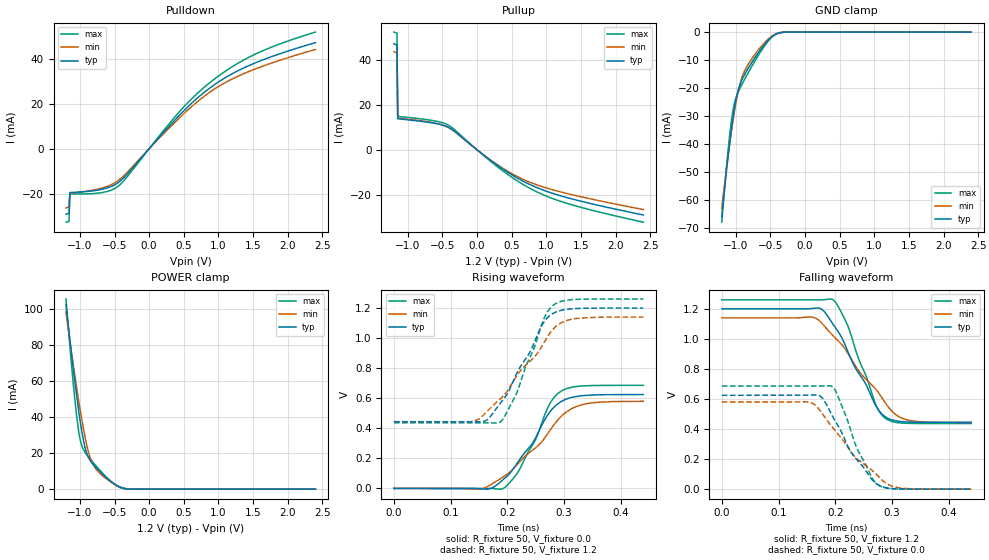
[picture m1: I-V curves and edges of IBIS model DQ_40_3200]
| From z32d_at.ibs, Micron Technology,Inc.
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| MODEL DQ_40_3200 (40 Ohm Data I/O with no ODT, 1600-3200Mbps)
[Model]   DQ_40_3200
Model_type   I/O
Vinl = 905.000mV
Vinh = 1015.000mV
Vmeas = 960.000mV
Vref = 1200.000mV
Cref = 0.0pF
Rref = 50.000Ohm
|   typ   min   max
|C_comp   0.636pF   0.586pF   0.686pF
C_comp_pullup   0.318pF   0.293pF   0.343pF
C_comp_pulldown   0.318pF   0.293pF   0.343pF
[Model Spec]
| Timing spec test load voltage corners
Vref   1.2000V   1.1400V   1.2600V
| Dynamic Overshoot Parameters from DDR4 Specification
|D_overshoot_ampl_h   0.40   NA   NA
|D_overshoot_ampl_l   0.40   NA   NA
|D_overshoot_area_h   0.0800n   NA   NA
|D_overshoot_area_l   0.0800n   NA   NA
[Voltage Range]   1.2000V   1.1400V   1.2600V
| Junction Temperature (Ambient temp is 35C typ, 105C min, -40C max)
[Temperature Range]   50.0   120.0   -40.0
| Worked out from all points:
|   slope of the pulldown table from 0 to 0.18 V, typ, clamps not added: 28.6 ohm
|   slope of the pullup table from 0 to 0.18 V, typ, clamps not added: 41.6 ohm
|   GND clamp passes 1 mA (typ) near -0.44 V on its own axis
|   POWER clamp passes 1 mA (typ) near -0.41 V on its own axis
|   rising waveform, R_fixture 50, V_fixture 0.0: 20-80 % time 63.6ps typ, 84.6ps min, 49.8ps max; typ from 0 V to 0.625 V
|   rising waveform, R_fixture 50, V_fixture 1.2: 20-80 % time 62.3ps typ, 85.6ps min, 48.6ps max; typ from 0.444 V to 1.2 V
|   falling waveform, R_fixture 50, V_fixture 1.2: 20-80 % time 61.1ps typ, 85.3ps min, 46.3ps max; typ from 1.2 V to 0.444 V
|   falling waveform, R_fixture 50, V_fixture 0.0: 20-80 % time 60.7ps typ, 83.5ps min, 45.1ps max; typ from 0.625 V to 0 V
[Pulldown]
|   Voltage   I(typ)   I(min)   I(max)
-1.2V     -29.12mA   -26.36mA   -32.71mA
-1.156V   -28.8mA    -26.03mA   -32.39mA
-1.145V   -19.51mA   -19.79mA   -20.16mA
-698.2mV  -18.17mA   -17.64mA   -19.61mA
-447.3mV  -15.08mA   -14.18mA   -16.69mA
-338.2mV  -11.99mA   -11.17mA   -13.27mA
469.1mV   15.9mA     14.67mA    17.58mA
698.2mV   22.62mA    20.99mA    24.73mA
938.2mV   28.41mA    26.49mA    30.92mA
1.211V    33.57mA    31.24mA    36.74mA
1.516V    38.02mA    35.32mA    41.88mA
2.4V      47.23mA    44.21mA    51.93mA
[GND Clamp]
|   Voltage   I(typ)   I(min)   I(max)
-1.2V     -66.16mA   -63.19mA   -68.09mA
-1.135V   -50.09mA   -49.27mA   -48.84mA
-1.091V   -40.55mA   -40.91mA   -37.85mA
-1.047V   -32.05mA   -33.18mA   -29.3mA
-1.004V   -25.21mA   -26.37mA   -24.13mA
-970.9mV  -21.44mA   -22.14mA   -21.89mA
-927.3mV  -18.1mA    -17.66mA   -19.59mA
-850.9mV  -14.3mA    -12.92mA   -15.99mA
-632.7mV  -6.061mA   -5.168mA   -6.759mA
-447.3mV  -1.181mA   -1.003mA   -1.122mA
-250.9mV  -9.403uA   -17.03uA   310.9nA
2.4V      0A         0A         0A
[Pullup]
|   Voltage   I(typ)   I(min)   I(max)
-1.2V     47.33mA    43.8mA     52.54mA
-1.156V   46.84mA    43.28mA    52.08mA
-1.145V   13.94mA    14.01mA    14.91mA
-676.4mV  12.17mA    12.32mA    13.24mA
-425.5mV  10.24mA    10.08mA    11.21mA
-316.4mV  8.104mA    7.94mA     8.758mA
43.64mV   -1.073mA   -1.039mA   -1.164mA
370.9mV   -8.572mA   -8.203mA   -9.376mA
621.8mV   -13.28mA   -12.55mA   -14.64mA
949.1mV   -17.88mA   -16.51mA   -19.98mA
1.462V    -22.63mA   -20.68mA   -25.34mA
2.4V      -29.08mA   -26.66mA   -32.28mA
[POWER Clamp]
|   Voltage   I(typ)   I(min)   I(max)
-1.2V     102.5mA    98.29mA    105.3mA
-1.135V   79.77mA    79.49mA    75.19mA
-1.069V   58.73mA    62.1mA     48.42mA
-1.015V   42.78mA    48.44mA    31.4mA
-981.8mV  34.36mA    40.79mA    25.35mA
-938.2mV  25.27mA    31.47mA    21.3mA
-905.5mV  20.47mA    25.33mA    19.42mA
-818.2mV  14.14mA    14.34mA    15.22mA
-709.1mV  9.665mA    8.746mA    10.4mA
-501.8mV  2.908mA    2.683mA    2.742mA
-250.9mV  22.56uA    45.53uA    -929.3nA
2.4V      0A         0A         0A
[Ramp]
|   typ   min   max
| 20% - 80%
dV/dt_r   374.75m/63.58p   347.77m/84.56p   411.51m/49.80p
dV/dt_f   453.55m/61.15p   417.79m/85.32p   494.02m/46.29p
| Slew rate: Power terminated
|SR_r[V/ns]   7.28   4.88   10.18
|SR_f[V/ns]   7.42   4.90   10.67
| 25% - 75%
|dV/dt_r   312.29m/52.61p   289.81m/70.66p   342.92m/41.18p
|dV/dt_f   377.96m/50.69p   348.16m/70.02p   411.68m/38.60p
| Slew rate: Power terminated
|SR_r[V/ns]   7.36   4.93   10.29
|SR_f[V/ns]   7.46   4.97   10.67
R_load = 50
[Rising Waveform]
R_fixture = 50
V_fixture = 0.0
|   Time   V(typ)   V(min)   V(max)
0s        6.048uV    19.72uV    354.8nV
151ps     -1.811mV   -3.906mV   40.26uV
172ps     1.347mV    26.69mV    -349.1uV
192ps     56.09mV    74.04mV    -1.218mV
220ps     183mV      170.1mV    115.4mV
250ps     337mV      270.6mV    326.1mV
273ps     498.3mV    374.4mV    549.3mV
292ps     570.9mV    467.2mV    639.7mV
336ps     618.4mV    560.6mV    682.6mV
440ps     624.6mV    579.6mV    685.8mV
[Rising Waveform]
R_fixture   = 50
V_fixture   = 1.2
V_fixture_min = 1.14
V_fixture_max = 1.26
|   Time   V(typ)   V(min)   V(max)
0s        444.1mV    443.6mV    436.6mV
140ps     443.6mV    446.5mV    436.6mV
164ps     455.2mV    511.7mV    436.6mV
187ps     563.5mV    593.3mV    440.8mV
215ps     752.6mV    739.8mV    620.5mV
240ps     907.8mV    846.2mV    872.8mV
264ps     1.104V     965mV      1.125V
280ps     1.163V     1.056V     1.216V
320ps     1.197V     1.13V      1.257V
440ps     1.2V       1.14V      1.26V
[Falling Waveform]
R_fixture   = 50
V_fixture   = 1.2
V_fixture_min = 1.14
V_fixture_max = 1.26
|   Time   V(typ)   V(min)   V(max)
0s        1.2V       1.14V      1.26V
159ps     1.202V     1.145V     1.26V
176ps     1.198V     1.106V     1.26V
195ps     1.104V     1.025V     1.263V
220ps     936.8mV    918.6mV    1.107V
270ps     566.7mV    672.3mV    576.6mV
286ps     487.8mV    587.6mV    478.6mV
305ps     456.3mV    501.5mV    445.8mV
328ps     446.7mV    460.1mV    438.1mV
440ps     444.1mV    443.7mV    436.6mV
[Falling Waveform]
R_fixture = 50
V_fixture = 0.0
|   Time   V(typ)   V(min)   V(max)
0s        624.6mV    579.8mV    685.9mV
154ps     625.9mV    578.5mV    685.8mV
175ps     614.8mV    514.1mV    686.2mV
193ps     500.6mV    420.5mV    685.8mV
203ps     434.8mV    376.1mV    635mV
229ps     239.7mV    241.7mV    371.7mV
241ps     184.3mV    194.6mV    251.2mV
275ps     29.84mV    88.51mV    30.16mV
313ps     1.736mV    9.083mV    942.9uV
440ps     6.181uV    24.11uV    369nV
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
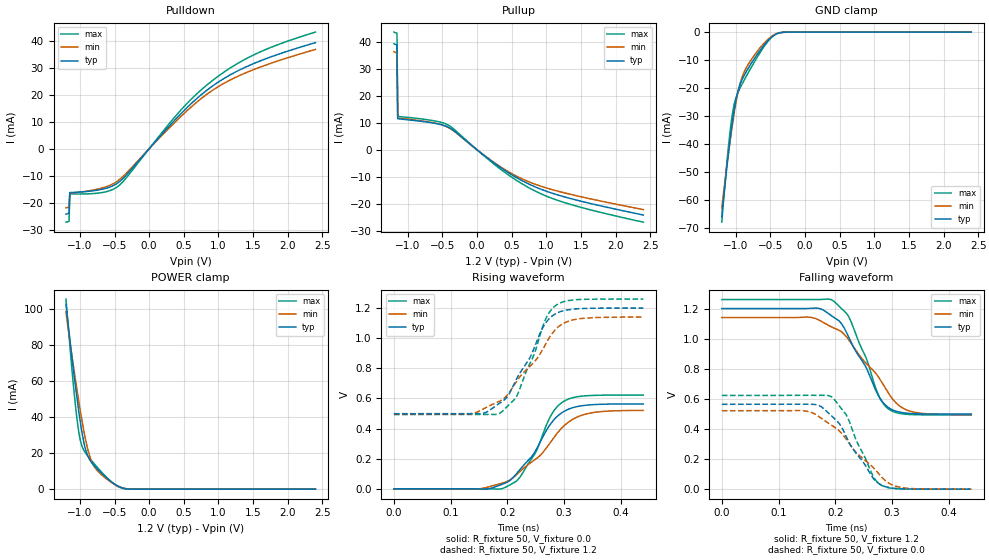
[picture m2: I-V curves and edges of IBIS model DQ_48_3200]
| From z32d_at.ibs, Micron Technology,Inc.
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| MODEL DQ_48_3200 (48 Ohm Data I/O with no ODT, 1600-3200Mbps)
[Model]   DQ_48_3200
Model_type   I/O
Vinl = 905.000mV
Vinh = 1015.000mV
Vmeas = 960.000mV
Vref = 1200.000mV
Cref = 0.0pF
Rref = 50.000Ohm
|   typ   min   max
|C_comp   0.636pF   0.586pF   0.686pF
C_comp_pullup   0.318pF   0.293pF   0.343pF
C_comp_pulldown   0.318pF   0.293pF   0.343pF
[Model Spec]
| Timing spec test load voltage corners
Vref   1.2000V   1.1400V   1.2600V
| Dynamic Overshoot Parameters from DDR4 Specification
|D_overshoot_ampl_h   0.40   NA   NA
|D_overshoot_ampl_l   0.40   NA   NA
|D_overshoot_area_h   0.0800n   NA   NA
|D_overshoot_area_l   0.0800n   NA   NA
[Voltage Range]   1.2000V   1.1400V   1.2600V
| Junction Temperature (Ambient temp is 35C typ, 105C min, -40C max)
[Temperature Range]   50.0   120.0   -40.0
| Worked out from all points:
|   slope of the pulldown table from 0 to 0.18 V, typ, clamps not added: 34.3 ohm
|   slope of the pullup table from 0 to 0.18 V, typ, clamps not added: 49.8 ohm
|   GND clamp passes 1 mA (typ) near -0.44 V on its own axis
|   POWER clamp passes 1 mA (typ) near -0.41 V on its own axis
|   rising waveform, R_fixture 50, V_fixture 0.0: 20-80 % time 61.7ps typ, 80.3ps min, 48.6ps max; typ from 0 V to 0.564 V
|   rising waveform, R_fixture 50, V_fixture 1.2: 20-80 % time 56.5ps typ, 74.9ps min, 45ps max; typ from 0.499 V to 1.2 V
|   falling waveform, R_fixture 50, V_fixture 1.2: 20-80 % time 56.4ps typ, 75.9ps min, 45.2ps max; typ from 1.2 V to 0.499 V
|   falling waveform, R_fixture 50, V_fixture 0.0: 20-80 % time 56.3ps typ, 79.4ps min, 43.6ps max; typ from 0.564 V to 0 V
[Pulldown]
|   Voltage   I(typ)   I(min)   I(max)
-1.2V     -24.27mA   -21.97mA   -27.26mA
-1.156V   -24mA      -21.69mA   -26.99mA
-1.145V   -16.26mA   -16.49mA   -16.8mA
-665.5mV  -14.96mA   -14.47mA   -16.2mA
-534.5mV  -13.86mA   -13.19mA   -15.23mA
-436.4mV  -12.37mA   -11.61mA   -13.68mA
425.5mV   12.1mA     11.15mA    13.4mA
643.6mV   17.6mA     16.3mA     19.29mA
927.3mV   23.48mA    21.9mA     25.55mA
1.2V      27.83mA    25.89mA    30.45mA
1.527V    31.8mA     29.55mA    35.03mA
2.4V      39.36mA    36.85mA    43.27mA
[GND Clamp]
|   Voltage   I(typ)   I(min)   I(max)
-1.2V     -66.16mA   -63.19mA   -68.09mA
-1.135V   -50.09mA   -49.27mA   -48.85mA
-1.091V   -40.54mA   -40.91mA   -37.85mA
-1.058V   -34.05mA   -35.04mA   -31.11mA
-1.015V   -26.75mA   -27.97mA   -25.14mA
-970.9mV  -21.46mA   -22.07mA   -21.88mA
-938.2mV  -18.78mA   -18.62mA   -20.13mA
-861.8mV  -14.78mA   -13.45mA   -16.49mA
-654.5mV  -6.796mA   -5.82mA    -7.607mA
-458.2mV  -1.354mA   -1.154mA   -1.328mA
-261.8mV  -15.07uA   -22.38uA   -1.874uA
2.4V      0A         0A         0A
[Pullup]
|   Voltage   I(typ)   I(min)   I(max)
-1.2V     39.44mA    36.5mA     43.78mA
-1.156V   39.03mA    36.07mA    43.4mA
-1.145V   11.61mA    11.67mA    12.43mA
-654.5mV  10.06mA    10.17mA    10.94mA
-425.5mV  8.536mA    8.416mA    9.339mA
-327.3mV  6.972mA    6.829mA    7.536mA
54.55mV   -1.117mA   -1.08mA    -1.215mA
381.8mV   -7.325mA   -7.008mA   -8.015mA
687.3mV   -11.95mA   -11.24mA   -13.21mA
949.1mV   -14.91mA   -13.76mA   -16.65mA
1.462V    -18.86mA   -17.23mA   -21.12mA
2.4V      -24.24mA   -22.22mA   -26.9mA
[POWER Clamp]
|   Voltage   I(typ)   I(min)   I(max)
-1.2V     102.5mA    98.29mA    105.3mA
-1.135V   79.77mA    79.49mA    75.19mA
-1.069V   58.73mA    62.1mA     48.4mA
-1.015V   42.76mA    48.44mA    31.44mA
-981.8mV  34.37mA    40.78mA    25.34mA
-938.2mV  25.23mA    31.42mA    21.29mA
-905.5mV  20.47mA    25.3mA     19.42mA
-818.2mV  14.14mA    14.34mA    15.22mA
-709.1mV  9.665mA    8.746mA    10.4mA
-501.8mV  2.9mA      2.681mA    2.745mA
-261.8mV  34uA       56.74uA    4.604uA
2.4V      0A         0A         0A
[Ramp]
|   typ   min   max
| 20% - 80%
dV/dt_r   338.19m/61.67p   312.42m/80.31p   373.57m/48.65p
dV/dt_f   420.87m/56.38p   386.39m/75.92p   460.07m/45.24p
| Slew rate: Power terminated
|SR_r[V/ns]   7.46   5.16   10.22
|SR_f[V/ns]   7.46   5.09   10.17
| 25% - 75%
|dV/dt_r   281.82m/49.79p   260.35m/66.06p   311.31m/39.25p
|dV/dt_f   350.73m/47.52p   321.99m/64.22p   383.39m/37.68p
| Slew rate: Power terminated
|SR_r[V/ns]   7.39   5.07   10.20
|SR_f[V/ns]   7.38   5.01   10.17
R_load = 50
[Rising Waveform]
R_fixture = 50
V_fixture = 0.0
|   Time   V(typ)   V(min)   V(max)
0s        6.769uV    21.94uV    398.2nV
146ps     -811.3uV   -1.787mV   8.918uV
193ps     32.9mV     39.55mV    3.811mV
207ps     62.53mV    64.93mV    30.62mV
223ps     131.7mV    116.7mV    80.82mV
251ps     260.6mV    199.4mV    248.6mV
277ps     433.9mV    313.8mV    486.6mV
298ps     509.5mV    410.4mV    577.1mV
343ps     556.6mV    500.4mV    618.8mV
440ps     563.7mV    520.7mV    622.6mV
[Rising Waveform]
R_fixture   = 50
V_fixture   = 1.2
V_fixture_min = 1.14
V_fixture_max = 1.26
|   Time   V(typ)   V(min)   V(max)
0s        498.5mV    495.9mV    493.2mV
135ps     498.3mV    498mV      493.2mV
186ps     566.9mV    580.6mV    500.2mV
201ps     616.4mV    627.6mV    551.7mV
217ps     734.3mV    717.2mV    618.8mV
248ps     939.9mV    843.6mV    899.5mV
267ps     1.098V     957.6mV    1.122V
286ps     1.164V     1.062V     1.219V
330ps     1.197V     1.131V     1.258V
440ps     1.2V       1.14V      1.26V
[Falling Waveform]
R_fixture   = 50
V_fixture   = 1.2
V_fixture_min = 1.14
V_fixture_max = 1.26
|   Time   V(typ)   V(min)   V(max)
0s        1.2V       1.14V      1.26V
153ps     1.201V     1.143V     1.26V
193ps     1.153V     1.079V     1.259V
211ps     1.1V       1.046V     1.2V
224ps     1.008V     991.8mV    1.145V
255ps     804.3mV    834.2mV    867mV
275ps     629.7mV    752.1mV    635.9mV
292ps     547.6mV    648.3mV    538.7mV
332ps     502.8mV    518.3mV    495.8mV
440ps     498.5mV    496mV      493.2mV
[Falling Waveform]
R_fixture = 50
V_fixture = 0.0
|   Time   V(typ)   V(min)   V(max)
0s        563.7mV    521.1mV    622.6mV
147ps     564.2mV    519.4mV    622.6mV
171ps     556.2mV    482.4mV    622.9mV
191ps     495.2mV    431.5mV    618.5mV
208ps     431.6mV    383.8mV    548.8mV
220ps     344.5mV    328.7mV    489.3mV
265ps     83.15mV    151.2mV    100.1mV
280ps     30.02mV    88.21mV    29.53mV
320ps     1.953mV    9.203mV    1.095mV
440ps     7.785uV    31.9uV     515.6nV
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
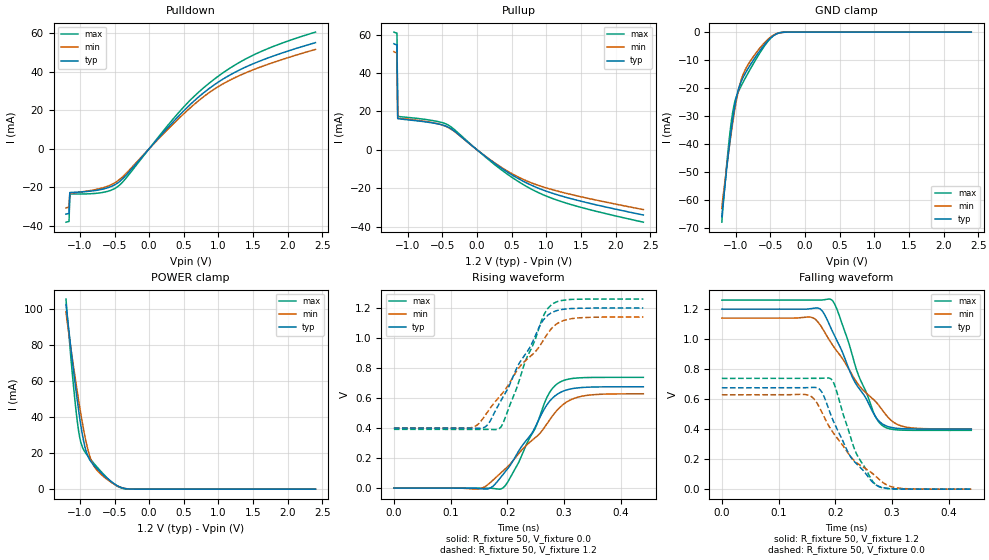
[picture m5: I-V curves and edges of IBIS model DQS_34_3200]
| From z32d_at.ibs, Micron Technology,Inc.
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| MODEL DQS_34_3200 (34 Ohm Data Strobe I/O with no ODT, 1600-3200Mbps)
[Model]   DQS_34_3200
Model_type   I/O
Vinl = 905.000mV
Vinh = 1015.000mV
Vmeas = 960.000mV
Vref = 1200.000mV
Cref = 0.0pF
Rref = 50.000Ohm
|   typ   min   max
|C_comp   0.636pF   0.586pF   0.686pF
C_comp_pullup   0.318pF   0.293pF   0.343pF
C_comp_pulldown   0.318pF   0.293pF   0.343pF
[Model Spec]
| Timing spec test load voltage corners
Vref   1.2000V   1.1400V   1.2600V
| Dynamic Overshoot Parameters from DDR4 Specification
|D_overshoot_ampl_h   0.40   NA   NA
|D_overshoot_ampl_l   0.40   NA   NA
|D_overshoot_area_h   0.0800n   NA   NA
|D_overshoot_area_l   0.0800n   NA   NA
[Voltage Range]   1.2000V   1.1400V   1.2600V
| Junction Temperature (Ambient temp is 35C typ, 105C min, -40C max)
[Temperature Range]   50.0   120.0   -40.0
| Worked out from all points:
|   slope of the pulldown table from 0 to 0.18 V, typ, clamps not added: 24.5 ohm
|   slope of the pullup table from 0 to 0.18 V, typ, clamps not added: 35.6 ohm
|   GND clamp passes 1 mA (typ) near -0.44 V on its own axis
|   POWER clamp passes 1 mA (typ) near -0.41 V on its own axis
|   rising waveform, R_fixture 50, V_fixture 0.0: 20-80 % time 65.4ps typ, 88.3ps min, 51.3ps max; typ from 0 V to 0.675 V
|   rising waveform, R_fixture 50, V_fixture 1.2: 20-80 % time 66.8ps typ, 91.7ps min, 51.8ps max; typ from 0.4 V to 1.2 V
|   falling waveform, R_fixture 50, V_fixture 1.2: 20-80 % time 63.8ps typ, 89ps min, 48.9ps max; typ from 1.2 V to 0.4 V
|   falling waveform, R_fixture 50, V_fixture 0.0: 20-80 % time 59ps typ, 80.5ps min, 44.9ps max; typ from 0.676 V to 0 V
[Pulldown]
|   Voltage   I(typ)   I(min)   I(max)
-1.2V     -33.97mA   -30.75mA   -38.16mA
-1.156V   -33.6mA    -30.37mA   -37.79mA
-1.145V   -22.76mA   -23.09mA   -23.52mA
-665.5mV  -20.94mA   -20.25mA   -22.68mA
-534.5mV  -19.41mA   -18.46mA   -21.32mA
-436.4mV  -17.3mA    -16.23mA   -19.17mA
447.3mV   17.75mA    16.36mA    19.64mA
687.3mV   26.05mA    24.16mA    28.48mA
960mV     33.69mA    31.42mA    36.67mA
1.222V    39.38mA    36.64mA    43.11mA
1.527V    44.52mA    41.36mA    49.04mA
2.4V      55.1mA     51.58mA    60.58mA
[GND Clamp]
|   Voltage   I(typ)   I(min)   I(max)
-1.2V     -66.16mA   -63.19mA   -68.09mA
-1.135V   -50.09mA   -49.27mA   -48.84mA
-1.091V   -40.54mA   -40.91mA   -37.85mA
-1.047V   -32.06mA   -33.18mA   -29.28mA
-1.004V   -25.24mA   -26.41mA   -24.15mA
-960mV    -20.46mA   -20.87mA   -21.27mA
-927.3mV  -18.11mA   -17.71mA   -19.59mA
-840mV    -13.84mA   -12.43mA   -15.5mA
-632.7mV  -6.06mA    -5.168mA   -6.758mA
-458.2mV  -1.359mA   -1.153mA   -1.332mA
-250.9mV  -9.002uA   -15.24uA   1.741uA
2.4V      0A         0A         0A
[Pullup]
|   Voltage   I(typ)   I(min)   I(max)
-1.2V     55.21mA    51.1mA     61.29mA
-1.156V   54.64mA    50.49mA    60.76mA
-1.145V   16.26mA    16.34mA    17.4mA
-643.6mV  14.02mA    14.17mA    15.25mA
-414.5mV  11.76mA    11.58mA    12.86mA
-316.4mV  9.458mA    9.262mA    10.21mA
87.27mV   -2.487mA   -2.407mA   -2.71mA
403.6mV   -10.78mA   -10.31mA   -11.8mA
643.6mV   -15.92mA   -15.01mA   -17.57mA
960mV     -21.02mA   -19.39mA   -23.48mA
1.484V    -26.6mA    -24.3mA    -29.78mA
2.4V      -33.93mA   -31.11mA   -37.66mA
[POWER Clamp]
|   Voltage   I(typ)   I(min)   I(max)
-1.2V     102.5mA    98.29mA    105.3mA
-1.135V   79.77mA    79.49mA    75.19mA
-1.08V    62.13mA    64.93mA    52.54mA
-1.036V   48.91mA    53.79mA    37.32mA
-992.7mV  37.04mA    43.27mA    27.02mA
-916.4mV  21.89mA    27.24mA    20mA
-861.8mV  16.57mA    18.83mA    17.26mA
-818.2mV  14.14mA    14.37mA    15.22mA
-720mV    10.08mA    9.153mA    10.86mA
-512.7mV  3.198mA    2.931mA    3.061mA
-250.9mV  21.9uA     40.66uA    -1.736uA
2.4V      0A         0A         0A
[Ramp]
|   typ   min   max
| 20% - 80%
dV/dt_r   405.29m/65.42p   377.33m/88.34p   442.96m/51.27p
dV/dt_f   479.80m/63.86p   443.25m/88.97p   520.92m/48.87p
| Slew rate: Power terminated
|SR_r[V/ns]   7.18   4.83   10.05
|SR_f[V/ns]   7.51   4.98   10.66
| 25% - 75%
|dV/dt_r   337.74m/54.25p   314.44m/73.48p   369.13m/42.54p
|dV/dt_f   399.83m/53.48p   369.38m/74.60p   434.10m/40.83p
| Slew rate: Power terminated
|SR_r[V/ns]   7.13   4.75   9.99
|SR_f[V/ns]   7.48   4.95   10.63
R_load = 50
[Rising Waveform]
R_fixture = 50
V_fixture = 0.0
|   Time   V(typ)   V(min)   V(max)
0s        5.466uV    18.08uV    320nV
150ps     -2.78mV    -5.018mV   66.59uV
171ps     2.747mV    40.23mV    -649.6uV
190ps     79.57mV    106.5mV    -3.675mV
217ps     227.7mV    215.5mV    148mV
250ps     412.1mV    337.3mV    405.2mV
270ps     555.5mV    429.1mV    605.2mV
287ps     622.8mV    515.6mV    691.8mV
332ps     670.6mV    612.8mV    735.9mV
440ps     675.5mV    628.9mV    738.3mV
[Rising Waveform]
R_fixture   = 50
V_fixture   = 1.2
V_fixture_min = 1.14
V_fixture_max = 1.26
|   Time   V(typ)   V(min)   V(max)
0s        400.3mV    401.2mV    391.8mV
139ps     399.6mV    405.4mV    391.8mV
164ps     417mV      501.4mV    391.7mV
185ps     557.9mV    603.9mV    395.1mV
194ps     615.4mV    644.6mV    446mV
222ps     838mV      809.6mV    729.4mV
259ps     1.094V     957.7mV    1.102V
276ps     1.164V     1.055V     1.216V
314ps     1.197V     1.13V      1.258V
440ps     1.2V       1.14V      1.26V
[Falling Waveform]
R_fixture   = 50
V_fixture   = 1.2
V_fixture_min = 1.14
V_fixture_max = 1.26
|   Time   V(typ)   V(min)   V(max)
0s        1.2V       1.14V      1.26V
156ps     1.203V     1.147V     1.26V
175ps     1.196V     1.086V     1.26V
192ps     1.077V     979.4mV    1.265V
205ps     974.9mV    910mV      1.18V
233ps     725.6mV    741.1mV    853.4mV
268ps     502mV      596.5mV    507.4mV
281ps     440.7mV    538mV      430.7mV
322ps     402.4mV    415.9mV    392.9mV
440ps     400.3mV    401.2mV    391.8mV
[Falling Waveform]
R_fixture = 50
V_fixture = 0.0
|   Time   V(typ)   V(min)   V(max)
0s        675.5mV    629mV      738.3mV
152ps     677.1mV    627.1mV    738.2mV
174ps     659.6mV    531mV      738.8mV
191ps     507.9mV    407.1mV    738mV
200ps     426.2mV    357.6mV    682.6mV
224ps     235.1mV    233.3mV    385.9mV
236ps     175mV      181.6mV    248.3mV
272ps     28.24mV    84.62mV    28.54mV
310ps     1.328mV    7.821mV    665.5uV
440ps     5.568uV    20.22uV    4.257uV
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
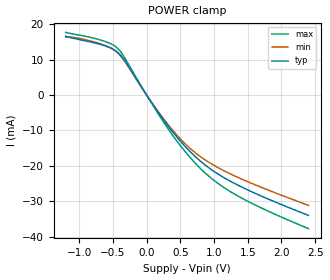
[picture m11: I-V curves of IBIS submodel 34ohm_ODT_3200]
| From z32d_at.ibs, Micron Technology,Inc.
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| SUBMODEL 34ohm_ODT_3200
[Submodel]   34ohm_ODT_3200
Submodel_type  Dynamic_clamp
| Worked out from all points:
|   POWER clamp passes 1 mA (typ) near -0.03 V on its own axis
[POWER Clamp]
|   Voltage   I(typ)   I(min)   I(max)
-1.2V     16.56mA    16.3mA     17.64mA
-730mV    14.48mA    14.7mA     15.74mA
-550mV    13.39mA    13.42mA    14.6mA
-425mV    11.94mA    11.77mA    13.06mA
-320mV    9.561mA    9.361mA    10.33mA
155mV     -4.371mA   -4.217mA   -4.773mA
425mV     -11.28mA   -10.78mA   -12.35mA
660mV     -16.23mA   -15.29mA   -17.92mA
965mV     -21.08mA   -19.44mA   -23.56mA
1.23V     -24.17mA   -22.12mA   -27.09mA
1.495V    -26.7mA    -24.39mA   -29.9mA
2.4V      -33.93mA   -31.11mA   -37.66mA
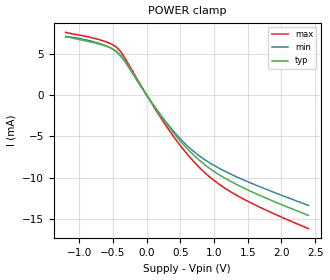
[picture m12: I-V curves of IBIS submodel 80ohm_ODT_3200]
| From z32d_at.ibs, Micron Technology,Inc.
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| SUBMODEL 80ohm_ODT_3200
[Submodel]   80ohm_ODT_3200
Submodel_type  Dynamic_clamp
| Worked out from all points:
|   POWER clamp passes 1 mA (typ) near -0.08 V on its own axis
[POWER Clamp]
|   Voltage   I(typ)   I(min)   I(max)
-1.2V     7.095mA    6.996mA    7.561mA
-690mV    6.119mA    6.199mA    6.654mA
-530mV    5.667mA    5.668mA    6.187mA
-425mV    5.113mA    5.047mA    5.599mA
-310mV    3.976mA    3.894mA    4.293mA
140mV     -1.698mA   -1.637mA   -1.85mA
405mV     -4.635mA   -4.433mA   -5.074mA
695mV     -7.235mA   -6.795mA   -8.001mA
935mV     -8.863mA   -8.187mA   -9.898mA
1.17V     -10.08mA   -9.242mA   -11.3mA
1.485V    -11.41mA   -10.42mA   -12.77mA
2.4V      -14.54mA   -13.33mA   -16.14mA
